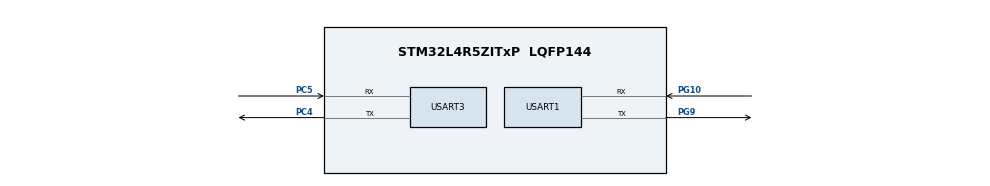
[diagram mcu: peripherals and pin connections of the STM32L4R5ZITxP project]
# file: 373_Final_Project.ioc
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Dma.Request0=USART1_RX
Dma.USART1_RX.0.Direction=DMA_PERIPH_TO_MEMORY
Dma.USART1_RX.0.EventEnable=DISABLE
Dma.USART1_RX.0.Instance=DMA1_Channel1
Dma.USART1_RX.0.MemDataAlignment=DMA_MDATAALIGN_BYTE
Dma.USART1_RX.0.MemInc=DMA_MINC_ENABLE
Dma.USART1_RX.0.Mode=DMA_NORMAL
Dma.USART1_RX.0.PeriphDataAlignment=DMA_PDATAALIGN_BYTE
Dma.USART1_RX.0.PeriphInc=DMA_PINC_DISABLE
Dma.USART1_RX.0.Polarity=HAL_DMAMUX_REQUEST_GEN_RISING
Dma.USART1_RX.0.Priority=DMA_PRIORITY_HIGH
Dma.USART1_RX.0.RequestNumber=1
Dma.USART1_RX.0.SignalID=NONE
Dma.USART1_RX.0.SyncEnable=DISABLE
Dma.USART1_RX.0.SyncPolarity=HAL_DMAMUX_SYNC_NO_EVENT
Dma.USART1_RX.0.SyncRequestNumber=1
Dma.USART1_RX.0.SyncSignalID=NONE
Mcu.Family=STM32L4
Mcu.Name=STM32L4R5ZITxP
Mcu.Package=LQFP144
NVIC.DMA1_Channel1_IRQn=true\:2\:0\:true\:false\:true\:false\:true\:true
NVIC.PriorityGroup=NVIC_PRIORITYGROUP_4
PA0.Signal=S_TIM2_CH1
PA1.Signal=ADCx_IN6
PA10.Signal=USB_OTG_FS_ID
PA13\ (JTMS/SWDIO).Signal=SYS_JTMS-SWDIO
PA14\ (JTCK/SWCLK).Signal=SYS_JTCK-SWCLK
PA3.Signal=ADCx_IN8
PA4.Signal=SPI1_NSS
PA5.Signal=SPI1_SCK
PA6.Signal=SPI1_MISO
PA7.Signal=SPI1_MOSI
PA8.Signal=USB_OTG_FS_SOF
PA9.Signal=USB_OTG_FS_VBUS
PB0.Signal=S_TIM3_CH3
PB1.Signal=ADCx_IN16
PB10.Signal=S_TIM2_CH3
PB12.Signal=SAI2_FS_A
PB13.Signal=SAI2_SCK_A
PB14.Signal=S_TIM15_CH1
PB15.Signal=SAI2_SD_A
PB2.Signal=COMP1_INP
PB3\ (JTDO/TRACESWO).Signal=SPI3_SCK
PB4\ (NJTRST).Signal=SPI3_MISO
PB5.Signal=SPI3_MOSI
PB6.Signal=COMP2_INP
PB8.Signal=I2C1_SCL
PB9.Signal=I2C1_SDA
PC0.Signal=ADCx_IN1
PC1.Signal=ADCx_IN2
PC10.Signal=SDMMC1_D2
PC11.Signal=SDMMC1_D3
PC12.Signal=SDMMC1_CK
PC13.Signal=SYS_WKUP2
PC14-OSC32_IN\ (PC14).Signal=RCC_OSC32_IN
PC15-OSC32_OUT\ (PC15).Signal=RCC_OSC32_OUT
PC2.Signal=ADCx_IN3
PC3.Signal=ADCx_IN4
PC4.Mode=Asynchronous
PC4.Signal=USART3_TX
PC5.Mode=Asynchronous
PC5.Signal=USART3_RX
PC6.Signal=SAI2_MCLK_A
PC7.Signal=S_TIM3_CH2
PC8.Signal=SDMMC1_D0
PC9.Signal=SDMMC1_D1
PD0.Signal=CAN1_RX
PD14.Signal=S_TIM4_CH3
PD15.Signal=S_TIM4_CH4
PD2.Signal=SDMMC1_CMD
PD3.Signal=USART2_CTS
PD4.Signal=USART2_RTS
PD5.Signal=USART2_TX
PD6.Signal=USART2_RX
PE0.Signal=S_TIM4_ETR
PE10.Signal=TIM1_CH2N
PE11.Signal=S_TIM1_CH2
PE12.Signal=TIM1_CH3N
PE13.Signal=S_TIM1_CH3
PE14.Signal=TIM1_BKIN2
PE15.Signal=TIM1_BKIN
PE2.Signal=SAI1_MCLK_A
PE3.Signal=SAI1_SD_B
PE7.Signal=S_TIM1_ETR
PE8.Signal=TIM1_CH1N
PE9.Signal=S_TIM1_CH1
PF0.Signal=I2C2_SDA
PF1.Signal=I2C2_SCL
PF2.Signal=I2C2_SMBA
PF7.Signal=SAI1_MCLK_B
PG10.Mode=Asynchronous
PG10.Signal=USART1_RX
PG7.Signal=LPUART1_TX
PG8.Signal=LPUART1_RX
PG9.Mode=Asynchronous
PG9.Signal=USART1_TX
PH0-OSC_IN\ (PH0).Signal=RCC_OSC_IN
PH1-OSC_OUT\ (PH1).Signal=RCC_OSC_OUT
ProjectManager.HeapSize=0x200
ProjectManager.StackSize=0x400
ProjectManager.TargetToolchain=STM32CubeIDE
RCC.AHBFreq_Value=80000000
RCC.APB1Freq_Value=80000000
RCC.APB1TimFreq_Value=80000000
RCC.APB2Freq_Value=80000000
RCC.APB2TimFreq_Value=80000000
RCC.CortexFreq_Value=80000000
RCC.HCLKFreq_Value=80000000
RCC.HSE_VALUE=8000000
RCC.HSI48_VALUE=48000000
RCC.HSI_VALUE=16000000
RCC.LSE_VALUE=32768
RCC.MSI_VALUE=4000000
RCC.PLLN=40
RCC.SYSCLKFreq_VALUE=80000000
RCC.SYSCLKSource=RCC_SYSCLKSOURCE_PLLCLK
RCC.VCOOutputFreq_Value=160000000
SH.ADCx_IN1.0=ADC1_IN1
SH.ADCx_IN16.0=ADC1_IN16
SH.ADCx_IN2.0=ADC1_IN2
SH.ADCx_IN3.0=ADC1_IN3
SH.ADCx_IN4.0=ADC1_IN4
SH.ADCx_IN6.0=ADC1_IN6
SH.ADCx_IN8.0=ADC1_IN8
SH.S_TIM15_CH1.0=TIM15_CH1
SH.S_TIM1_CH1.0=TIM1_CH1
SH.S_TIM1_CH2.0=TIM1_CH2
SH.S_TIM1_CH3.0=TIM1_CH3
SH.S_TIM1_ETR.0=TIM1_ETR
SH.S_TIM2_CH1.0=TIM2_CH1
SH.S_TIM2_CH3.0=TIM2_CH3
SH.S_TIM3_CH2.0=TIM3_CH2
SH.S_TIM3_CH3.0=TIM3_CH3
SH.S_TIM4_CH3.0=TIM4_CH3
SH.S_TIM4_CH4.0=TIM4_CH4
SH.S_TIM4_ETR.0=TIM4_ETR
USART1.VirtualMode-Asynchronous=VM_ASYNC
USART3.VirtualMode-Asynchronous=VM_ASYNC
USART3.WordLength=WORDLENGTH_8B
board=NUCLEO-L4R5ZI-P

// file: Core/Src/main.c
/* USER CODE BEGIN Header */
/**
  ******************************************************************************
  * @file           : main.c
  * @brief          : Main program body
  ******************************************************************************
  * @attention
  *
  * Copyright (c) 2025 STMicroelectronics.
  * All rights reserved.
  *
  * This software is licensed under terms that can be found in the LICENSE file
  * in the root directory of this software component.
  * If no LICENSE file comes with this software, it is provided AS-IS.
  *
  ******************************************************************************
  */
/* USER CODE END Header */
#include "main.h"

UART_HandleTypeDef huart1;
UART_HandleTypeDef huart3;
DMA_HandleTypeDef hdma_usart1_rx;

/* USER CODE BEGIN PV */
uint8_t capsule_data[168];
/* USER CODE END PV */

void SystemClock_Config(void);
static void MX_GPIO_Init(void);
static void MX_DMA_Init(void);
static void MX_USART1_UART_Init(void);
static void MX_USART3_UART_Init(void);

int main(void)
{

  /* MCU Configuration--------------------------------------------------------*/

  /* Reset of all peripherals, Initializes the Flash interface and the Systick. */
  HAL_Init();

  /* USER CODE BEGIN Init */
  uint8_t capsule_data[84];
  /* USER CODE END Init */

  /* Configure the system clock */
  SystemClock_Config();

  /* Initialize all configured peripherals */
  MX_GPIO_Init();
  MX_DMA_Init();
  MX_USART1_UART_Init();
  MX_USART3_UART_Init();
  /* USER CODE BEGIN 2 */
  send_express_scan_command(&huart3);
  HAL_Delay(1000);
  /* USER CODE END 2 */

  /* Infinite loop */
  /* USER CODE BEGIN WHILE */
  while (1)
  {
	 HAL_UART_Receive(&huart3, capsule_data, sizeof(capsule_data), HAL_MAX_DELAY);
	 decode_express_capsule(capsule_data);
    /* USER CODE END WHILE */

  }
}

void SystemClock_Config(void)
{
  RCC_OscInitTypeDef RCC_OscInitStruct = {0};
  RCC_ClkInitTypeDef RCC_ClkInitStruct = {0};

  /** Configure the main internal regulator output voltage
  */
  if (HAL_PWREx_ControlVoltageScaling(PWR_REGULATOR_VOLTAGE_SCALE1) != HAL_OK)
  {
    Error_Handler();
  }

  /** Initializes the RCC Oscillators according to the specified parameters
  * in the RCC_OscInitTypeDef structure.
  */
  RCC_OscInitStruct.OscillatorType = RCC_OSCILLATORTYPE_MSI;
  RCC_OscInitStruct.MSIState = RCC_MSI_ON;
  RCC_OscInitStruct.MSICalibrationValue = 0;
  RCC_OscInitStruct.MSIClockRange = RCC_MSIRANGE_6;
  RCC_OscInitStruct.PLL.PLLState = RCC_PLL_NONE;
  if (HAL_RCC_OscConfig(&RCC_OscInitStruct) != HAL_OK)
  {
    Error_Handler();
  }

  /** Initializes the CPU, AHB and APB buses clocks
  */
  RCC_ClkInitStruct.ClockType = RCC_CLOCKTYPE_HCLK|RCC_CLOCKTYPE_SYSCLK
                              |RCC_CLOCKTYPE_PCLK1|RCC_CLOCKTYPE_PCLK2;
  RCC_ClkInitStruct.SYSCLKSource = RCC_SYSCLKSOURCE_MSI;
  RCC_ClkInitStruct.AHBCLKDivider = RCC_SYSCLK_DIV1;
  RCC_ClkInitStruct.APB1CLKDivider = RCC_HCLK_DIV1;
  RCC_ClkInitStruct.APB2CLKDivider = RCC_HCLK_DIV1;

  if (HAL_RCC_ClockConfig(&RCC_ClkInitStruct, FLASH_LATENCY_0) != HAL_OK)
  {
    Error_Handler();
  }
}

static void MX_USART1_UART_Init(void)
{

  huart1.Instance = USART1;
  huart1.Init.BaudRate = 115200;
  huart1.Init.WordLength = UART_WORDLENGTH_8B;
  huart1.Init.StopBits = UART_STOPBITS_1;
  huart1.Init.Parity = UART_PARITY_NONE;
  huart1.Init.Mode = UART_MODE_TX_RX;
  huart1.Init.HwFlowCtl = UART_HWCONTROL_NONE;
  huart1.Init.OverSampling = UART_OVERSAMPLING_16;
  huart1.Init.OneBitSampling = UART_ONE_BIT_SAMPLE_DISABLE;
  huart1.Init.ClockPrescaler = UART_PRESCALER_DIV1;
  huart1.AdvancedInit.AdvFeatureInit = UART_ADVFEATURE_NO_INIT;
  if (HAL_UART_Init(&huart1) != HAL_OK)
  {
    Error_Handler();
  }
  if (HAL_UARTEx_SetTxFifoThreshold(&huart1, UART_TXFIFO_THRESHOLD_1_8) != HAL_OK)
  {
    Error_Handler();
  }
  if (HAL_UARTEx_SetRxFifoThreshold(&huart1, UART_RXFIFO_THRESHOLD_1_8) != HAL_OK)
  {
    Error_Handler();
  }
  if (HAL_UARTEx_DisableFifoMode(&huart1) != HAL_OK)
  {
    Error_Handler();
  }

}

static void MX_USART3_UART_Init(void)
{

  huart3.Instance = USART3;
  huart3.Init.BaudRate = 115200;
  huart3.Init.WordLength = UART_WORDLENGTH_8B;
  huart3.Init.StopBits = UART_STOPBITS_1;
  huart3.Init.Parity = UART_PARITY_NONE;
  huart3.Init.Mode = UART_MODE_TX_RX;
  huart3.Init.HwFlowCtl = UART_HWCONTROL_NONE;
  huart3.Init.OverSampling = UART_OVERSAMPLING_16;
  huart3.Init.OneBitSampling = UART_ONE_BIT_SAMPLE_DISABLE;
  huart3.Init.ClockPrescaler = UART_PRESCALER_DIV1;
  huart3.AdvancedInit.AdvFeatureInit = UART_ADVFEATURE_NO_INIT;
  if (HAL_UART_Init(&huart3) != HAL_OK)
  {
    Error_Handler();
  }
  if (HAL_UARTEx_SetTxFifoThreshold(&huart3, UART_TXFIFO_THRESHOLD_1_8) != HAL_OK)
  {
    Error_Handler();
  }
  if (HAL_UARTEx_SetRxFifoThreshold(&huart3, UART_RXFIFO_THRESHOLD_1_8) != HAL_OK)
  {
    Error_Handler();
  }
  if (HAL_UARTEx_DisableFifoMode(&huart3) != HAL_OK)
  {
    Error_Handler();
  }

}

static void MX_DMA_Init(void)
{

  /* DMA controller clock enable */
  __HAL_RCC_DMAMUX1_CLK_ENABLE();
  __HAL_RCC_DMA1_CLK_ENABLE();

  /* DMA interrupt init */
  /* DMA1_Channel1_IRQn interrupt configuration */
  HAL_NVIC_SetPriority(DMA1_Channel1_IRQn, 2, 0);
  HAL_NVIC_EnableIRQ(DMA1_Channel1_IRQn);

}

static void MX_GPIO_Init(void)
{
  GPIO_InitTypeDef GPIO_InitStruct = {0};

  /* GPIO Ports Clock Enable */
  __HAL_RCC_GPIOE_CLK_ENABLE();
  __HAL_RCC_GPIOC_CLK_ENABLE();
  __HAL_RCC_GPIOF_CLK_ENABLE();
  __HAL_RCC_GPIOH_CLK_ENABLE();
  __HAL_RCC_GPIOA_CLK_ENABLE();
  __HAL_RCC_GPIOB_CLK_ENABLE();
  __HAL_RCC_GPIOD_CLK_ENABLE();
  __HAL_RCC_GPIOG_CLK_ENABLE();
  HAL_PWREx_EnableVddIO2();

  /*Configure GPIO pins : PE2 PE3 */
  GPIO_InitStruct.Pin = GPIO_PIN_2|GPIO_PIN_3;
  GPIO_InitStruct.Mode = GPIO_MODE_AF_PP;
  GPIO_InitStruct.Pull = GPIO_NOPULL;
  GPIO_InitStruct.Speed = GPIO_SPEED_FREQ_LOW;
  GPIO_InitStruct.Alternate = GPIO_AF13_SAI1;
  HAL_GPIO_Init(GPIOE, &GPIO_InitStruct);

  /*Configure GPIO pins : PF0 PF1 PF2 */
  GPIO_InitStruct.Pin = GPIO_PIN_0|GPIO_PIN_1|GPIO_PIN_2;
  GPIO_InitStruct.Mode = GPIO_MODE_AF_OD;
  GPIO_InitStruct.Pull = GPIO_NOPULL;
  GPIO_InitStruct.Speed = GPIO_SPEED_FREQ_VERY_HIGH;
  GPIO_InitStruct.Alternate = GPIO_AF4_I2C2;
  HAL_GPIO_Init(GPIOF, &GPIO_InitStruct);

  /*Configure GPIO pin : PF7 */
  GPIO_InitStruct.Pin = GPIO_PIN_7;
  GPIO_InitStruct.Mode = GPIO_MODE_AF_PP;
  GPIO_InitStruct.Pull = GPIO_NOPULL;
  GPIO_InitStruct.Speed = GPIO_SPEED_FREQ_LOW;
  GPIO_InitStruct.Alternate = GPIO_AF13_SAI1;
  HAL_GPIO_Init(GPIOF, &GPIO_InitStruct);

  /*Configure GPIO pins : PC0 PC1 PC2 PC3
                           PC4 PC5 */
  GPIO_InitStruct.Pin = GPIO_PIN_0|GPIO_PIN_1|GPIO_PIN_2|GPIO_PIN_3
                          |GPIO_PIN_4|GPIO_PIN_5;
  GPIO_InitStruct.Mode = GPIO_MODE_ANALOG_ADC_CONTROL;
  GPIO_InitStruct.Pull = GPIO_NOPULL;
  HAL_GPIO_Init(GPIOC, &GPIO_InitStruct);

  /*Configure GPIO pin : PA0 */
  GPIO_InitStruct.Pin = GPIO_PIN_0;
  GPIO_InitStruct.Mode = GPIO_MODE_AF_PP;
  GPIO_InitStruct.Pull = GPIO_NOPULL;
  GPIO_InitStruct.Speed = GPIO_SPEED_FREQ_LOW;
  GPIO_InitStruct.Alternate = GPIO_AF1_TIM2;
  HAL_GPIO_Init(GPIOA, &GPIO_InitStruct);

  /*Configure GPIO pins : PA1 PA3 */
  GPIO_InitStruct.Pin = GPIO_PIN_1|GPIO_PIN_3;
  GPIO_InitStruct.Mode = GPIO_MODE_ANALOG_ADC_CONTROL;
  GPIO_InitStruct.Pull = GPIO_NOPULL;
  HAL_GPIO_Init(GPIOA, &GPIO_InitStruct);

  /*Configure GPIO pins : PA4 PA5 PA6 PA7 */
  GPIO_InitStruct.Pin = GPIO_PIN_4|GPIO_PIN_5|GPIO_PIN_6|GPIO_PIN_7;
  GPIO_InitStruct.Mode = GPIO_MODE_AF_PP;
  GPIO_InitStruct.Pull = GPIO_NOPULL;
  GPIO_InitStruct.Speed = GPIO_SPEED_FREQ_VERY_HIGH;
  GPIO_InitStruct.Alternate = GPIO_AF5_SPI1;
  HAL_GPIO_Init(GPIOA, &GPIO_InitStruct);

  /*Configure GPIO pin : PB0 */
  GPIO_InitStruct.Pin = GPIO_PIN_0;
  GPIO_InitStruct.Mode = GPIO_MODE_AF_PP;
  GPIO_InitStruct.Pull = GPIO_NOPULL;
  GPIO_InitStruct.Speed = GPIO_SPEED_FREQ_LOW;
  GPIO_InitStruct.Alternate = GPIO_AF2_TIM3;
  HAL_GPIO_Init(GPIOB, &GPIO_InitStruct);

  /*Configure GPIO pin : PB1 */
  GPIO_InitStruct.Pin = GPIO_PIN_1;
  GPIO_InitStruct.Mode = GPIO_MODE_ANALOG_ADC_CONTROL;
  GPIO_InitStruct.Pull = GPIO_NOPULL;
  HAL_GPIO_Init(GPIOB, &GPIO_InitStruct);

  /*Configure GPIO pins : PB2 PB6 */
  GPIO_InitStruct.Pin = GPIO_PIN_2|GPIO_PIN_6;
  GPIO_InitStruct.Mode = GPIO_MODE_ANALOG;
  GPIO_InitStruct.Pull = GPIO_NOPULL;
  HAL_GPIO_Init(GPIOB, &GPIO_InitStruct);

  /*Configure GPIO pins : PE7 PE8 PE9 PE10
                           PE11 PE12 PE13 */
  GPIO_InitStruct.Pin = GPIO_PIN_7|GPIO_PIN_8|GPIO_PIN_9|GPIO_PIN_10
                          |GPIO_PIN_11|GPIO_PIN_12|GPIO_PIN_13;
  GPIO_InitStruct.Mode = GPIO_MODE_AF_PP;
  GPIO_InitStruct.Pull = GPIO_NOPULL;
  GPIO_InitStruct.Speed = GPIO_SPEED_FREQ_LOW;
  GPIO_InitStruct.Alternate = GPIO_AF1_TIM1;
  HAL_GPIO_Init(GPIOE, &GPIO_InitStruct);

  /*Configure GPIO pins : PE14 PE15 */
  GPIO_InitStruct.Pin = GPIO_PIN_14|GPIO_PIN_15;
  GPIO_InitStruct.Mode = GPIO_MODE_AF_PP;
  GPIO_InitStruct.Pull = GPIO_NOPULL;
  GPIO_InitStruct.Speed = GPIO_SPEED_FREQ_LOW;
  GPIO_InitStruct.Alternate = GPIO_AF3_TIM1_COMP1;
  HAL_GPIO_Init(GPIOE, &GPIO_InitStruct);

  /*Configure GPIO pin : PB10 */
  GPIO_InitStruct.Pin = GPIO_PIN_10;
  GPIO_InitStruct.Mode = GPIO_MODE_AF_PP;
  GPIO_InitStruct.Pull = GPIO_NOPULL;
  GPIO_InitStruct.Speed = GPIO_SPEED_FREQ_LOW;
  GPIO_InitStruct.Alternate = GPIO_AF1_TIM2;
  HAL_GPIO_Init(GPIOB, &GPIO_InitStruct);

  /*Configure GPIO pins : PB12 PB13 PB15 */
  GPIO_InitStruct.Pin = GPIO_PIN_12|GPIO_PIN_13|GPIO_PIN_15;
  GPIO_InitStruct.Mode = GPIO_MODE_AF_PP;
  GPIO_InitStruct.Pull = GPIO_NOPULL;
  GPIO_InitStruct.Speed = GPIO_SPEED_FREQ_LOW;
  GPIO_InitStruct.Alternate = GPIO_AF13_SAI2;
  HAL_GPIO_Init(GPIOB, &GPIO_InitStruct);

  /*Configure GPIO pin : PB14 */
  GPIO_InitStruct.Pin = GPIO_PIN_14;
  GPIO_InitStruct.Mode = GPIO_MODE_AF_PP;
  GPIO_InitStruct.Pull = GPIO_NOPULL;
  GPIO_InitStruct.Speed = GPIO_SPEED_FREQ_LOW;
  GPIO_InitStruct.Alternate = GPIO_AF14_TIM15;
  HAL_GPIO_Init(GPIOB, &GPIO_InitStruct);

  /*Configure GPIO pins : PD14 PD15 */
  GPIO_InitStruct.Pin = GPIO_PIN_14|GPIO_PIN_15;
  GPIO_InitStruct.Mode = GPIO_MODE_AF_PP;
  GPIO_InitStruct.Pull = GPIO_NOPULL;
  GPIO_InitStruct.Speed = GPIO_SPEED_FREQ_LOW;
  GPIO_InitStruct.Alternate = GPIO_AF2_TIM4;
  HAL_GPIO_Init(GPIOD, &GPIO_InitStruct);

  /*Configure GPIO pins : PG7 PG8 */
  GPIO_InitStruct.Pin = GPIO_PIN_7|GPIO_PIN_8;
  GPIO_InitStruct.Mode = GPIO_MODE_AF_PP;
  GPIO_InitStruct.Pull = GPIO_NOPULL;
  GPIO_InitStruct.Speed = GPIO_SPEED_FREQ_VERY_HIGH;
  GPIO_InitStruct.Alternate = GPIO_AF8_LPUART1;
  HAL_GPIO_Init(GPIOG, &GPIO_InitStruct);

  /*Configure GPIO pin : PC6 */
  GPIO_InitStruct.Pin = GPIO_PIN_6;
  GPIO_InitStruct.Mode = GPIO_MODE_AF_PP;
  GPIO_InitStruct.Pull = GPIO_NOPULL;
  GPIO_InitStruct.Speed = GPIO_SPEED_FREQ_LOW;
  GPIO_InitStruct.Alternate = GPIO_AF13_SAI2;
  HAL_GPIO_Init(GPIOC, &GPIO_InitStruct);

  /*Configure GPIO pin : PC7 */
  GPIO_InitStruct.Pin = GPIO_PIN_7;
  GPIO_InitStruct.Mode = GPIO_MODE_AF_PP;
  GPIO_InitStruct.Pull = GPIO_NOPULL;
  GPIO_InitStruct.Speed = GPIO_SPEED_FREQ_LOW;
  GPIO_InitStruct.Alternate = GPIO_AF2_TIM3;
  HAL_GPIO_Init(GPIOC, &GPIO_InitStruct);

  /*Configure GPIO pins : PC8 PC9 PC10 PC11
                           PC12 */
  GPIO_InitStruct.Pin = GPIO_PIN_8|GPIO_PIN_9|GPIO_PIN_10|GPIO_PIN_11
                          |GPIO_PIN_12;
  GPIO_InitStruct.Mode = GPIO_MODE_AF_PP;
  GPIO_InitStruct.Pull = GPIO_NOPULL;
  GPIO_InitStruct.Speed = GPIO_SPEED_FREQ_VERY_HIGH;
  GPIO_InitStruct.Alternate = GPIO_AF12_SDMMC1;
  HAL_GPIO_Init(GPIOC, &GPIO_InitStruct);

  /*Configure GPIO pins : PA8 PA10 */
  GPIO_InitStruct.Pin = GPIO_PIN_8|GPIO_PIN_10;
  GPIO_InitStruct.Mode = GPIO_MODE_AF_PP;
  GPIO_InitStruct.Pull = GPIO_NOPULL;
  GPIO_InitStruct.Speed = GPIO_SPEED_FREQ_VERY_HIGH;
  GPIO_InitStruct.Alternate = GPIO_AF10_OTG_FS;
  HAL_GPIO_Init(GPIOA, &GPIO_InitStruct);

  /*Configure GPIO pin : PA9 */
  GPIO_InitStruct.Pin = GPIO_PIN_9;
  GPIO_InitStruct.Mode = GPIO_MODE_INPUT;
  GPIO_InitStruct.Pull = GPIO_NOPULL;
  HAL_GPIO_Init(GPIOA, &GPIO_InitStruct);

  /*Configure GPIO pin : PD0 */
  GPIO_InitStruct.Pin = GPIO_PIN_0;
  GPIO_InitStruct.Mode = GPIO_MODE_AF_PP;
  GPIO_InitStruct.Pull = GPIO_NOPULL;
  GPIO_InitStruct.Speed = GPIO_SPEED_FREQ_VERY_HIGH;
  GPIO_InitStruct.Alternate = GPIO_AF9_CAN1;
  HAL_GPIO_Init(GPIOD, &GPIO_InitStruct);

  /*Configure GPIO pin : PD2 */
  GPIO_InitStruct.Pin = GPIO_PIN_2;
  GPIO_InitStruct.Mode = GPIO_MODE_AF_PP;
  GPIO_InitStruct.Pull = GPIO_NOPULL;
  GPIO_InitStruct.Speed = GPIO_SPEED_FREQ_VERY_HIGH;
  GPIO_InitStruct.Alternate = GPIO_AF12_SDMMC1;
  HAL_GPIO_Init(GPIOD, &GPIO_InitStruct);

  /*Configure GPIO pins : PD3 PD4 PD5 PD6 */
  GPIO_InitStruct.Pin = GPIO_PIN_3|GPIO_PIN_4|GPIO_PIN_5|GPIO_PIN_6;
  GPIO_InitStruct.Mode = GPIO_MODE_AF_PP;
  GPIO_InitStruct.Pull = GPIO_NOPULL;
  GPIO_InitStruct.Speed = GPIO_SPEED_FREQ_VERY_HIGH;
  GPIO_InitStruct.Alternate = GPIO_AF7_USART2;
  HAL_GPIO_Init(GPIOD, &GPIO_InitStruct);

  /*Configure GPIO pins : PB3 PB4 PB5 */
  GPIO_InitStruct.Pin = GPIO_PIN_3|GPIO_PIN_4|GPIO_PIN_5;
  GPIO_InitStruct.Mode = GPIO_MODE_AF_PP;
  GPIO_InitStruct.Pull = GPIO_NOPULL;
  GPIO_InitStruct.Speed = GPIO_SPEED_FREQ_VERY_HIGH;
  GPIO_InitStruct.Alternate = GPIO_AF6_SPI3;
  HAL_GPIO_Init(GPIOB, &GPIO_InitStruct);

  /*Configure GPIO pins : PB8 PB9 */
  GPIO_InitStruct.Pin = GPIO_PIN_8|GPIO_PIN_9;
  GPIO_InitStruct.Mode = GPIO_MODE_AF_OD;
  GPIO_InitStruct.Pull = GPIO_NOPULL;
  GPIO_InitStruct.Speed = GPIO_SPEED_FREQ_VERY_HIGH;
  GPIO_InitStruct.Alternate = GPIO_AF4_I2C1;
  HAL_GPIO_Init(GPIOB, &GPIO_InitStruct);

  /*Configure GPIO pin : PE0 */
  GPIO_InitStruct.Pin = GPIO_PIN_0;
  GPIO_InitStruct.Mode = GPIO_MODE_AF_PP;
  GPIO_InitStruct.Pull = GPIO_NOPULL;
  GPIO_InitStruct.Speed = GPIO_SPEED_FREQ_LOW;
  GPIO_InitStruct.Alternate = GPIO_AF2_TIM4;
  HAL_GPIO_Init(GPIOE, &GPIO_InitStruct);

}

void Error_Handler(void)
{
  __disable_irq();
  while (1)
  {
  }
}
